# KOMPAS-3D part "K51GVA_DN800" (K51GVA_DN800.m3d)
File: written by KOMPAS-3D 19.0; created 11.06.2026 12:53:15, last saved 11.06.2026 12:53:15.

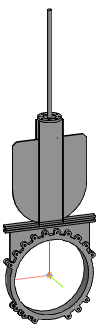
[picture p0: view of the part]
Document properties: Автор: Энергия; Полное имя файла: Z:\3.Личные\kachalov\001_3d для проектировщиков\2.6 Тип_K51GVA. Задвижка\_stp\_stp_K51GVA_DN50-DN1000_с фланцем\K51GVA_DN800.m3d

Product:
- Part/product: K51GVA_DN800

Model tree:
1. Операция без истории:1  (labels: K51GVA_DN800)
